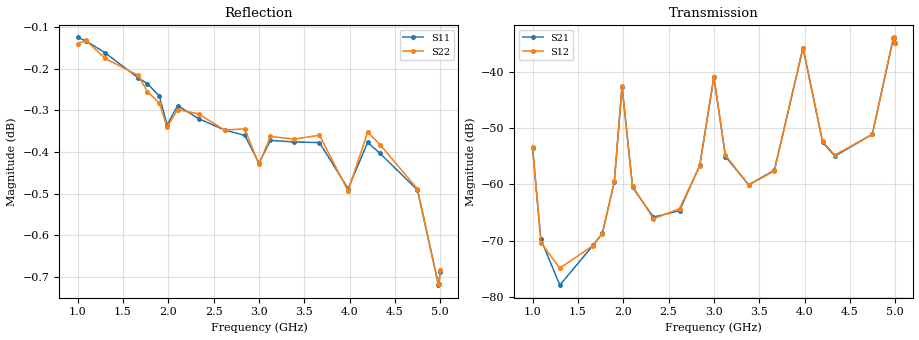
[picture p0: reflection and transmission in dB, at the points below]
!Keysight Technologies,N5242A,MY48420869,A.10.65.01
!Date: Wednesday, September 11, 2019 19:31:13
!Correction: S33(Full 4 Port(1,2,3,4))
!S43(Full 4 Port(1,2,3,4))
!S34(Full 4 Port(1,2,3,4))
!S44(Full 4 Port(1,2,3,4))
!S2P File: Measurements: S33, S43, S34, S44:
!Created with skrf (http://scikit-rf.org).
# Hz S RI R 50.0
!freq ReS11 ImS11 ReS21 ImS21 ReS12 ImS12 ReS22 ImS22
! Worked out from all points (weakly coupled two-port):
!   4001 points, 1 GHz to 5 GHz, reference 50 ohm
!   highest |S21| = -33.92 dB at 4.983 GHz (marker M1); lowest = -77.9 dB at 1.301 GHz (marker M2)
!   lowest |S11| = -0.7 dB at 4.98 GHz (marker M3), VSWR 24.13, Z = 2.16 - j10.3 ohm
!   |S11| at or under -10 dB: nowhere
!   |S22| runs from -0.7 to -0.1 dB; largest |S21 - S12| = 0.00055
!   S11 on the Smith chart (normalised r, x): 1 GHz: 0.01, -0.73; 1.77 GHz: 0.01, +0.06; 2.621 GHz: 0.04, +1.01; 3.384 GHz: 1.82, +8.95; 4.199 GHz: 0.06, -1.34; 5 GHz: 0.04, -0.19
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1e9  -0.3021 -0.9383  -0.00204 -0.000569  -0.00207 -0.000539  -0.3042 -0.9358
1.092e9  -0.4551 -0.8733  -0.000293 0.000139  -0.000274 0.000133  -0.459 -0.8714
1.301e9  -0.742 -0.6426  -8.67e-05 9.34e-05  -0.000117 0.000137  -0.7454 -0.6363
1.667e9  -0.9727 -0.0636  1.07e-05 0.000287  -8.87e-07 0.000286  -0.9738 -0.056
1.77e9  -0.9669 0.1104  6e-05 0.000362  7.85e-05 0.000357  -0.9635 0.1207
1.902e9  -0.9133 0.3263  0.000496 0.000919  0.00054 0.000933  -0.9076 0.3366
1.987e9  -0.8494 0.4519  0.0064 -0.00363  0.00648 -0.00363  -0.8438 0.4611
2.103e9  -0.7472 0.6143  -0.000529 -0.000777  -0.000591 -0.000764  -0.7372 0.6246
2.334e9  -0.4478 0.8535  -0.00044 -0.000262  -0.000438 -0.00023  -0.4326 0.8627
2.621e9  0.0133 0.9607  -0.000583 2.12e-05  -0.000605 7.03e-05  0.0309 0.9603
2.844e9  0.3758 0.8827  -0.00127 0.000747  -0.00125 0.000758  0.3934 0.8769
3e9  0.5911 0.7463  0.0088 0.00182  0.00882 0.00182  0.6065 0.7334
3.127e9  0.7485 0.598  0.00125 -0.00125  0.00129 -0.00129  0.7643 0.5794
3.384e9  0.9358 0.2033  0.000259 -0.000958  0.000219 -0.000963  0.9418 0.1775
3.667e9  0.9145 -0.2836  -0.000474 -0.00125  -0.000463 -0.00123  0.9091 -0.3066
3.983e9  0.6027 -0.7283  -0.0103 0.0126  -0.0104 0.0127  0.582 -0.7442
4.199e9  0.2765 -0.9167  0.00221 0.000852  0.00225 0.000872  0.2518 -0.9266
4.334e9  0.0378 -0.9539  0.00178 6.71e-05  0.00182 8.48e-05  0.0101 -0.9569
4.748e9  -0.6345 -0.7003  0.0018 -0.00213  0.00178 -0.00214  -0.6571 -0.6795
4.98e9  -0.8458 -0.3631  -0.0179 -0.00881  -0.018 -0.00892  -0.8573 -0.3355
4.983e9  -0.8474 -0.36  -0.0188 -0.00709  -0.0189 -0.00716  -0.8587 -0.3323
5e9  -0.8583 -0.3414  -0.0177 0.00265  -0.0178 0.00266  -0.8694 -0.3135
